# aion_layout: rewrote 'CLASS BLOCK ;' to 'CLASS CORE ;': magic reads no cell class out of a GDS and defaults to BLOCK, which OpenROAD treats as a hard macro
# aion_layout: inserted 'SITE CoreSite ;' after SIZE: magic emits no SITE, and without one the placer has no row to legalise the cell into
# aion_layout: inserted 'SYMMETRY X Y ;' after SIZE: magic emits no SYMMETRY, and without it the detailed placer will not put the cell in a flipped row
# aion_layout: inserted 'DIRECTION INPUT ;' on PIN I2: magic writes no pin direction, and a LEF pin without one is read as an input
# aion_layout: inserted 'DIRECTION INPUT ;' on PIN I3: magic writes no pin direction, and a LEF pin without one is read as an input
# aion_layout: inserted 'DIRECTION INPUT ;' on PIN I0: magic writes no pin direction, and a LEF pin without one is read as an input
# aion_layout: inserted 'DIRECTION INPUT ;' on PIN I1: magic writes no pin direction, and a LEF pin without one is read as an input
# aion_layout: inserted 'DIRECTION OUTPUT ;' on PIN O0: magic writes no pin direction, and a LEF pin without one is read as an input
# aion_layout: inserted 'DIRECTION INOUT ;' on PIN VDD: magic writes no pin direction, and a LEF pin without one is read as an input
# aion_layout: inserted 'DIRECTION INOUT ;' on PIN VSS: magic writes no pin direction, and a LEF pin without one is read as an input
VERSION 5.7 ;
  NOWIREEXTENSIONATPIN ON ;
  DIVIDERCHAR "/" ;
  BUSBITCHARS "[]" ;
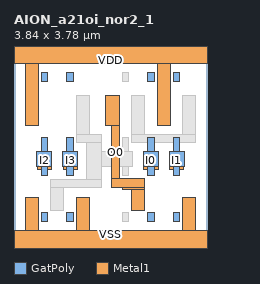
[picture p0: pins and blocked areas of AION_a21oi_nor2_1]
MACRO AION_a21oi_nor2_1
  CLASS CORE ;
  FOREIGN AION_a21oi_nor2_1 ;
  ORIGIN 0.000 0.000 ;
  SIZE 3.840 BY 3.780 ;
  SYMMETRY X Y ;
  SITE CoreSite ;
  PIN I2
    DIRECTION INPUT ;
    ANTENNAGATEAREA 0.241800 ;
    PORT
      LAYER GatPoly ;
        RECT 0.540 3.195 0.670 3.375 ;
        RECT 0.540 1.800 0.670 2.075 ;
        RECT 0.455 1.500 0.755 1.800 ;
        RECT 0.540 1.330 0.670 1.500 ;
        RECT 0.540 0.410 0.670 0.590 ;
      LAYER Metal1 ;
        RECT 0.465 1.450 0.745 1.790 ;
    END
  END I2
  PIN I3
    DIRECTION INPUT ;
    ANTENNAGATEAREA 0.241800 ;
    PORT
      LAYER GatPoly ;
        RECT 1.050 3.195 1.180 3.375 ;
        RECT 1.050 1.800 1.180 2.075 ;
        RECT 0.965 1.500 1.265 1.800 ;
        RECT 1.050 1.330 1.180 1.500 ;
        RECT 1.050 0.410 1.180 0.590 ;
      LAYER Metal1 ;
        RECT 0.975 1.450 1.255 1.790 ;
    END
  END I3
  PIN I0
    DIRECTION INPUT ;
    ANTENNAGATEAREA 0.241800 ;
    PORT
      LAYER GatPoly ;
        RECT 2.660 3.195 2.790 3.375 ;
        RECT 2.660 1.800 2.790 2.075 ;
        RECT 2.575 1.500 2.875 1.800 ;
        RECT 2.660 1.330 2.790 1.500 ;
        RECT 2.660 0.410 2.790 0.590 ;
      LAYER Metal1 ;
        RECT 2.585 1.450 2.865 1.790 ;
    END
  END I0
  PIN I1
    DIRECTION INPUT ;
    ANTENNAGATEAREA 0.241800 ;
    PORT
      LAYER GatPoly ;
        RECT 3.170 3.195 3.300 3.375 ;
        RECT 3.170 1.800 3.300 2.075 ;
        RECT 3.085 1.500 3.385 1.800 ;
        RECT 3.170 1.330 3.300 1.500 ;
        RECT 3.170 0.410 3.300 0.590 ;
      LAYER Metal1 ;
        RECT 3.095 1.450 3.375 1.790 ;
    END
  END I1
  PIN O0
    DIRECTION OUTPUT ;
    ANTENNADIFFAREA 0.706800 ;
    PORT
      LAYER Metal1 ;
        RECT 1.830 2.310 2.090 2.910 ;
        RECT 1.930 1.270 2.090 2.310 ;
        RECT 1.930 1.090 2.600 1.270 ;
        RECT 2.150 1.050 2.600 1.090 ;
        RECT 2.340 0.620 2.600 1.050 ;
    END
  END O0
  PIN VDD
    DIRECTION INOUT ;
    USE POWER ;
    PORT
      LAYER Metal1 ;
        RECT 0.000 3.560 3.840 4.000 ;
        RECT 0.220 2.310 0.480 3.560 ;
        RECT 2.850 2.310 3.110 3.560 ;
    END
  END VDD
  PIN VSS
    DIRECTION INOUT ;
    USE GROUND ;
    PORT
      LAYER Metal1 ;
        RECT 0.220 0.220 0.480 0.880 ;
        RECT 1.240 0.220 1.500 0.880 ;
        RECT 3.360 0.220 3.620 0.880 ;
        RECT 0.000 -0.220 3.840 0.220 ;
    END
  END VSS
  OBS
      LAYER GatPoly ;
        RECT 2.150 3.195 2.280 3.375 ;
        RECT 2.150 1.800 2.280 2.075 ;
        RECT 1.445 1.500 2.365 1.800 ;
        RECT 2.150 1.330 2.280 1.500 ;
        RECT 2.150 0.410 2.280 0.590 ;
      LAYER Metal1 ;
        RECT 1.240 2.130 1.500 2.910 ;
        RECT 2.340 2.130 2.600 2.910 ;
        RECT 3.360 2.130 3.620 2.910 ;
        RECT 1.240 1.970 1.750 2.130 ;
        RECT 2.340 1.970 3.620 2.130 ;
        RECT 1.450 1.250 1.750 1.970 ;
        RECT 0.730 1.090 1.750 1.250 ;
        RECT 0.730 0.620 0.990 1.090 ;
  END
END AION_a21oi_nor2_1
END LIBRARY

